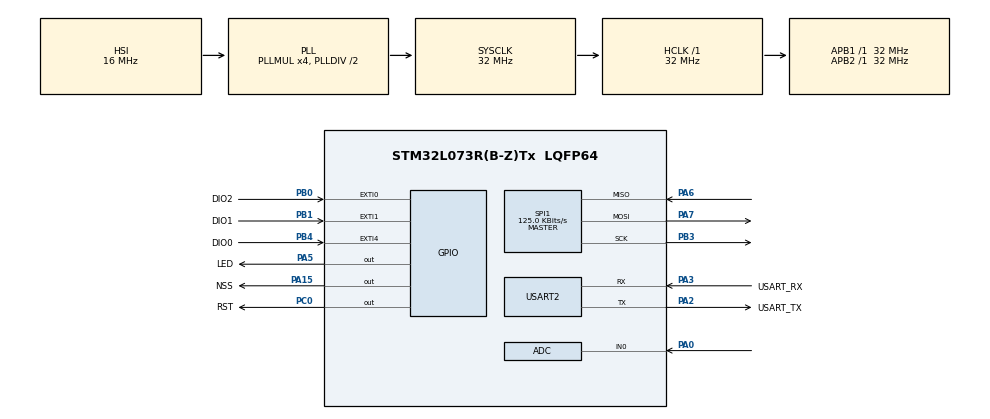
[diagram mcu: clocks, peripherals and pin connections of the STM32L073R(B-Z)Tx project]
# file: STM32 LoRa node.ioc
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Mcu.Family=STM32L0
Mcu.Name=STM32L073R(B-Z)Tx
Mcu.Package=LQFP64
NVIC.EXTI0_1_IRQn=true\:0\:0\:false\:false\:true\:true\:true
NVIC.EXTI4_15_IRQn=true\:0\:0\:false\:false\:true\:true\:true
NVIC.TIM21_IRQn=true\:0\:0\:false\:false\:true\:true\:true
PA0.Mode=IN0
PA0.Signal=ADC_IN0
PA13.GPIO_Label=TMS
PA13.Mode=Serial_Wire
PA13.Signal=SYS_SWDIO
PA14.GPIO_Label=TCK
PA14.Mode=Serial_Wire
PA14.Signal=SYS_SWCLK
PA15.GPIO_Label=NSS
PA15.Signal=GPIO_Output
PA2.GPIO_Label=USART_TX
PA2.Mode=Asynchronous
PA2.Signal=USART2_TX
PA3.GPIO_Label=USART_RX
PA3.Mode=Asynchronous
PA3.Signal=USART2_RX
PA5.GPIO_Label=LED
PA5.Signal=GPIO_Output
PA6.Mode=Full_Duplex_Master
PA6.Signal=SPI1_MISO
PA7.Mode=Full_Duplex_Master
PA7.Signal=SPI1_MOSI
PB0.GPIO_Label=DIO2
PB0.Signal=GPXTI0
PB1.GPIO_Label=DIO1
PB1.Signal=GPXTI1
PB3.Mode=Full_Duplex_Master
PB3.Signal=SPI1_SCK
PB4.GPIO_Label=DIO0
PB4.Signal=GPXTI4
PC0.GPIO_Label=RST
PC0.Signal=GPIO_Output
PC14-OSC32_IN.Mode=LSE-External-Oscillator
PC14-OSC32_IN.Signal=RCC_OSC32_IN
PC15-OSC32_OUT.Mode=LSE-External-Oscillator
PC15-OSC32_OUT.Signal=RCC_OSC32_OUT
ProjectManager.HeapSize=0x200
ProjectManager.StackSize=0x400
ProjectManager.TargetToolchain=STM32CubeIDE
RCC.AHBFreq_Value=32000000
RCC.APB1Freq_Value=32000000
RCC.APB1TimFreq_Value=32000000
RCC.APB2Freq_Value=32000000
RCC.APB2TimFreq_Value=32000000
RCC.HCLKFreq_Value=32000000
RCC.HSE_VALUE=8000000
RCC.HSI16_VALUE=16000000
RCC.HSI48_VALUE=48000000
RCC.HSI_VALUE=16000000
RCC.MSI_VALUE=2097000
RCC.PLLMUL=RCC_PLLMUL_4
RCC.SYSCLKFreq_VALUE=32000000
RCC.SYSCLKSource=RCC_SYSCLKSOURCE_PLLCLK
RCC.VCOOutputFreq_Value=64000000
SPI1.BaudRatePrescaler=SPI_BAUDRATEPRESCALER_256
SPI1.CalculateBaudRate=125.0 KBits/s
SPI1.Direction=SPI_DIRECTION_2LINES
SPI1.Mode=SPI_MODE_MASTER
SPI1.VirtualType=VM_MASTER
TIM21.Channel-Output\ Compare1\ No\ Output=TIM_CHANNEL_1
TIM21.Period=65535 - 1
TIM21.Prescaler=1000 - 1
USART2.VirtualMode-Asynchronous=VM_ASYNC
VP_TIM21_VS_ClockSourceINT.Mode=Internal
VP_TIM21_VS_no_output1.Mode=Output Compare1 No Output
board=NUCLEO-L073RZ

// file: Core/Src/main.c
/* USER CODE BEGIN Header */
/**
  ******************************************************************************
  * @file           : main.c
  * @brief          : Main program body
  ******************************************************************************
  * @attention
  *
  * <h2><center>&copy; Copyright (c) 2020 STMicroelectronics.
  * All rights reserved.</center></h2>
  *
  * This software component is licensed by ST under BSD 3-Clause license,
  * the "License"; You may not use this file except in compliance with the
  * License. You may obtain a copy of the License at:
  *                        opensource.org/licenses/BSD-3-Clause
  *
  ******************************************************************************
  */
/* USER CODE END Header */
#include "main.h"

/* USER CODE BEGIN Includes */
#include "lmic.h"
#include "sdp800.h"
#include "debug.h"
#include <stdio.h>
/* USER CODE END Includes */

ADC_HandleTypeDef hadc;

SPI_HandleTypeDef hspi1;

TIM_HandleTypeDef htim21;

UART_HandleTypeDef huart2;

/* USER CODE BEGIN PV */

Error error;
float diffPressure;
float temperature;

//int32_t temperature;
//uint32_t pressure, humidity;
//uint16_t battery_level;

__uint8_t repeat_period = 1; //number of seconds to wait before measurement loop repetition

/* Private variables ---------------------------------------------------------*/
// application router ID (LSBF)  < ------- IMPORTANT
static const u1_t APPEUI[8]  = { 0xB2, 0x5C, 0x03, 0xD0, 0x7E, 0xD5, 0xB3, 0x70 };
// unique device ID (LSBF)       < ------- IMPORTANT
static const u1_t DEVEUI[8]  = { 0x06, 0x14, 0xA0, 0x16, 0x20, 0xD4, 0x8A, 0x00 };

// device-specific AES key (derived from device EUI)
static const u1_t DEVKEY[16] = { 0x7A, 0x7F, 0x99, 0x33, 0xD6, 0x59, 0x1D, 0x6E, 0xDA, 0x75, 0x01, 0x19, 0x41, 0x64, 0x21, 0x44 };

/* USER CODE END PV */

void SystemClock_Config(void);
static void MX_GPIO_Init(void);
static void MX_USART2_UART_Init(void);
static void MX_SPI1_Init(void);
static void MX_TIM21_Init(void);
static void MX_ADC_Init(void);

/* USER CODE BEGIN 0 */
// provide application router ID (8 bytes, LSBF)
void os_getArtEui (u1_t* buf) {
    memcpy(buf, APPEUI, 8);
}

// provide device ID (8 bytes, LSBF)
void os_getDevEui (u1_t* buf) {
    memcpy(buf, DEVEUI, 8);
}

// provide device key (16 bytes)
void os_getDevKey (u1_t* buf) {
    memcpy(buf, DEVKEY, 16);
}

void initsensor(){
	// init sensors
	Sdp800_Init(0x25);
	Sdp800_SoftReset();
	error = Sdp800_StartContinousMeasurement(SDP800_TEMPCOMP_MASS_FLOW,
		                                             SDP800_AVERAGING_TILL_READ);
	if (error == ERROR_NONE)
		debug_str("SDP800 initialized\n\r");
	else
		debug_str("SDP800 failed to initialize\n\r");
}

void initfunc (osjob_t* j) {
    // intialize sensor hardware
    initsensor();
    // reset MAC state
    LMIC_reset();
    // start joining
    LMIC_startJoining();
    // init done - onEvent() callback will be invoked...
}

int readsensor(){
	error = Sdp800_ReadMeasurementResults(&diffPressure, &temperature);
	return error == ERROR_NONE;
}

static osjob_t reportjob;

// report sensor value every minute
static void reportfunc (osjob_t* j) {
	// read sensor
	if (readsensor()) {
		// if reading was a success:
		debug_str("Reading success: ");
		debug_f(diffPressure);
		debug_str(", ");
		debug_f(temperature);
		debug_str("\n\r");

		memcpy(LMIC.frame + 0, &diffPressure, 4);
		memcpy(LMIC.frame + 4, &temperature, 4);
		//}
	} else {
		// if reading was unsuccessful
		debug_str("Reading failed\n\r");

		for (int i = 0; i < 8; i++) {
			LMIC.frame[i] = 0xff; // error value
		}
	}

    LMIC_setTxData2(1, LMIC.frame, 8, 0); // (port 1, 8 bytes, unconfirmed)
    // reschedule job after 'repeat_period' seconds
    os_setTimedCallback(j, os_getTime()+sec2osticks(repeat_period), reportfunc);
}

//////////////////////////////////////////////////
// LMIC EVENT CALLBACK
//////////////////////////////////////////////////

void onEvent (ev_t ev) {
    debug_event(ev);

    switch(ev) {

      // network joined, session established
      case EV_JOINING:
       	  debug_str("try joining\r\n");
       	  break;
      case EV_JOINED:
          debug_led(1);
          // kick-off periodic sensor job
          reportfunc(&reportjob);
          break;
      case EV_JOIN_FAILED:
    	  debug_str("join failed\r\n");
    	  break;
      case EV_SCAN_TIMEOUT:
    	  debug_str("EV_SCAN_TIMEOUT\r\n");
		  break;
	  case EV_BEACON_FOUND:
		  debug_str("EV_BEACON_FOUND\r\n");
		  break;
	  case EV_BEACON_MISSED:
		  debug_str("EV_BEACON_MISSED\r\n");
		  break;
	  case EV_BEACON_TRACKED:
		  debug_str("EV_BEACON_TRACKED\r\n");
		  break;
	  case EV_RFU1:
		  debug_str("EV_RFU1\r\n");
		  break;
	  case EV_REJOIN_FAILED:
		  debug_str("EV_REJOIN_FAILED\r\n");
		  break;
	  case EV_TXCOMPLETE:
		  debug_str("EV_TXCOMPLETE (includes waiting for RX windows)\r\n");
		  if (LMIC.txrxFlags & TXRX_ACK)
			  debug_str("Received ack\r\n");
		  if (LMIC.dataLen) {
			  debug_str("Received ");
			  debug_int(LMIC.dataLen);
			  debug_str(" bytes of payload\r\n");
		  }
		  break;
	  case EV_LOST_TSYNC:
		  debug_str("EV_LOST_TSYNC\r\n");
		  break;
	  case EV_RESET:
		  debug_str("EV_RESET\r\n");
		  break;
	  case EV_RXCOMPLETE:
		  // data received in ping slot
		  debug_str("EV_RXCOMPLETE\r\n");
		  break;
	  case EV_LINK_DEAD:
		  debug_str("EV_LINK_DEAD\r\n");
		  break;
	  case EV_LINK_ALIVE:
		  debug_str("EV_LINK_ALIVE\r\n");
		  break;
	  default:
		   debug_str("Unknown event\r\n");
		  break;
    }
}
/* USER CODE END 0 */

int main(void)
{

  /* MCU Configuration--------------------------------------------------------*/

  /* Reset of all peripherals, Initializes the Flash interface and the Systick. */
  HAL_Init();

  /* Configure the system clock */
  SystemClock_Config();

  /* Initialize all configured peripherals */
  MX_GPIO_Init();
  MX_USART2_UART_Init();
  MX_SPI1_Init();
  MX_TIM21_Init();
  MX_ADC_Init();
  /* USER CODE BEGIN 2 */

  HAL_TIM_Base_Start_IT(&htim21);    // <-----------  change to your setup
   __HAL_SPI_ENABLE(&hspi1);         // <-----------  change to your setup

   osjob_t initjob;

   // initialize runtime env
   os_init();

   // initialize debug library
   debug_init();

   // setup initial job
   os_setCallback(&initjob, initfunc);

   Sdp800_Init(0x25); // initialize sensor module with address 0x25

   // execute scheduled jobs and events
   os_runloop();

   // (not reached)
   return 0;
  /* USER CODE END 2 */

  /* Infinite loop */
  while (1)
  {

	    	  }
}

void SystemClock_Config(void)
{
  RCC_OscInitTypeDef RCC_OscInitStruct = {0};
  RCC_ClkInitTypeDef RCC_ClkInitStruct = {0};
  RCC_PeriphCLKInitTypeDef PeriphClkInit = {0};

  /** Configure the main internal regulator output voltage
  */
  __HAL_PWR_VOLTAGESCALING_CONFIG(PWR_REGULATOR_VOLTAGE_SCALE1);
  /** Initializes the RCC Oscillators according to the specified parameters
  * in the RCC_OscInitTypeDef structure.
  */
  RCC_OscInitStruct.OscillatorType = RCC_OSCILLATORTYPE_HSI;
  RCC_OscInitStruct.HSIState = RCC_HSI_ON;
  RCC_OscInitStruct.HSICalibrationValue = RCC_HSICALIBRATION_DEFAULT;
  RCC_OscInitStruct.PLL.PLLState = RCC_PLL_ON;
  RCC_OscInitStruct.PLL.PLLSource = RCC_PLLSOURCE_HSI;
  RCC_OscInitStruct.PLL.PLLMUL = RCC_PLLMUL_4;
  RCC_OscInitStruct.PLL.PLLDIV = RCC_PLLDIV_2;
  if (HAL_RCC_OscConfig(&RCC_OscInitStruct) != HAL_OK)
  {
    Error_Handler();
  }
  /** Initializes the CPU, AHB and APB buses clocks
  */
  RCC_ClkInitStruct.ClockType = RCC_CLOCKTYPE_HCLK|RCC_CLOCKTYPE_SYSCLK
                              |RCC_CLOCKTYPE_PCLK1|RCC_CLOCKTYPE_PCLK2;
  RCC_ClkInitStruct.SYSCLKSource = RCC_SYSCLKSOURCE_PLLCLK;
  RCC_ClkInitStruct.AHBCLKDivider = RCC_SYSCLK_DIV1;
  RCC_ClkInitStruct.APB1CLKDivider = RCC_HCLK_DIV1;
  RCC_ClkInitStruct.APB2CLKDivider = RCC_HCLK_DIV1;

  if (HAL_RCC_ClockConfig(&RCC_ClkInitStruct, FLASH_LATENCY_1) != HAL_OK)
  {
    Error_Handler();
  }
  PeriphClkInit.PeriphClockSelection = RCC_PERIPHCLK_USART2;
  PeriphClkInit.Usart2ClockSelection = RCC_USART2CLKSOURCE_PCLK1;
  if (HAL_RCCEx_PeriphCLKConfig(&PeriphClkInit) != HAL_OK)
  {
    Error_Handler();
  }
}

static void MX_ADC_Init(void)
{

  ADC_ChannelConfTypeDef sConfig = {0};

  /** Configure the global features of the ADC (Clock, Resolution, Data Alignment and number of conversion)
  */
  hadc.Instance = ADC1;
  hadc.Init.OversamplingMode = DISABLE;
  hadc.Init.ClockPrescaler = ADC_CLOCK_SYNC_PCLK_DIV2;
  hadc.Init.Resolution = ADC_RESOLUTION_12B;
  hadc.Init.SamplingTime = ADC_SAMPLETIME_1CYCLE_5;
  hadc.Init.ScanConvMode = ADC_SCAN_DIRECTION_FORWARD;
  hadc.Init.DataAlign = ADC_DATAALIGN_RIGHT;
  hadc.Init.ContinuousConvMode = DISABLE;
  hadc.Init.DiscontinuousConvMode = DISABLE;
  hadc.Init.ExternalTrigConvEdge = ADC_EXTERNALTRIGCONVEDGE_NONE;
  hadc.Init.ExternalTrigConv = ADC_SOFTWARE_START;
  hadc.Init.DMAContinuousRequests = DISABLE;
  hadc.Init.EOCSelection = ADC_EOC_SINGLE_CONV;
  hadc.Init.Overrun = ADC_OVR_DATA_PRESERVED;
  hadc.Init.LowPowerAutoWait = DISABLE;
  hadc.Init.LowPowerFrequencyMode = DISABLE;
  hadc.Init.LowPowerAutoPowerOff = DISABLE;
  if (HAL_ADC_Init(&hadc) != HAL_OK)
  {
    Error_Handler();
  }
  /** Configure for the selected ADC regular channel to be converted.
  */
  sConfig.Channel = ADC_CHANNEL_0;
  sConfig.Rank = ADC_RANK_CHANNEL_NUMBER;
  if (HAL_ADC_ConfigChannel(&hadc, &sConfig) != HAL_OK)
  {
    Error_Handler();
  }

}

static void MX_SPI1_Init(void)
{

  /* SPI1 parameter configuration*/
  hspi1.Instance = SPI1;
  hspi1.Init.Mode = SPI_MODE_MASTER;
  hspi1.Init.Direction = SPI_DIRECTION_2LINES;
  hspi1.Init.DataSize = SPI_DATASIZE_8BIT;
  hspi1.Init.CLKPolarity = SPI_POLARITY_LOW;
  hspi1.Init.CLKPhase = SPI_PHASE_1EDGE;
  hspi1.Init.NSS = SPI_NSS_SOFT;
  hspi1.Init.BaudRatePrescaler = SPI_BAUDRATEPRESCALER_256;
  hspi1.Init.FirstBit = SPI_FIRSTBIT_MSB;
  hspi1.Init.TIMode = SPI_TIMODE_DISABLE;
  hspi1.Init.CRCCalculation = SPI_CRCCALCULATION_DISABLE;
  hspi1.Init.CRCPolynomial = 7;
  if (HAL_SPI_Init(&hspi1) != HAL_OK)
  {
    Error_Handler();
  }

}

static void MX_TIM21_Init(void)
{

  TIM_ClockConfigTypeDef sClockSourceConfig = {0};
  TIM_MasterConfigTypeDef sMasterConfig = {0};
  TIM_OC_InitTypeDef sConfigOC = {0};

  htim21.Instance = TIM21;
  htim21.Init.Prescaler = 1000 - 1;
  htim21.Init.CounterMode = TIM_COUNTERMODE_UP;
  htim21.Init.Period = 65535 - 1;
  htim21.Init.ClockDivision = TIM_CLOCKDIVISION_DIV1;
  htim21.Init.AutoReloadPreload = TIM_AUTORELOAD_PRELOAD_DISABLE;
  if (HAL_TIM_Base_Init(&htim21) != HAL_OK)
  {
    Error_Handler();
  }
  sClockSourceConfig.ClockSource = TIM_CLOCKSOURCE_INTERNAL;
  if (HAL_TIM_ConfigClockSource(&htim21, &sClockSourceConfig) != HAL_OK)
  {
    Error_Handler();
  }
  if (HAL_TIM_OC_Init(&htim21) != HAL_OK)
  {
    Error_Handler();
  }
  sMasterConfig.MasterOutputTrigger = TIM_TRGO_RESET;
  sMasterConfig.MasterSlaveMode = TIM_MASTERSLAVEMODE_DISABLE;
  if (HAL_TIMEx_MasterConfigSynchronization(&htim21, &sMasterConfig) != HAL_OK)
  {
    Error_Handler();
  }
  sConfigOC.OCMode = TIM_OCMODE_TIMING;
  sConfigOC.Pulse = 0;
  sConfigOC.OCPolarity = TIM_OCPOLARITY_HIGH;
  sConfigOC.OCFastMode = TIM_OCFAST_DISABLE;
  if (HAL_TIM_OC_ConfigChannel(&htim21, &sConfigOC, TIM_CHANNEL_1) != HAL_OK)
  {
    Error_Handler();
  }

}

static void MX_USART2_UART_Init(void)
{

  huart2.Instance = USART2;
  huart2.Init.BaudRate = 115200;
  huart2.Init.WordLength = UART_WORDLENGTH_8B;
  huart2.Init.StopBits = UART_STOPBITS_1;
  huart2.Init.Parity = UART_PARITY_NONE;
  huart2.Init.Mode = UART_MODE_TX_RX;
  huart2.Init.HwFlowCtl = UART_HWCONTROL_NONE;
  huart2.Init.OverSampling = UART_OVERSAMPLING_16;
  huart2.Init.OneBitSampling = UART_ONE_BIT_SAMPLE_DISABLE;
  huart2.AdvancedInit.AdvFeatureInit = UART_ADVFEATURE_NO_INIT;
  if (HAL_UART_Init(&huart2) != HAL_OK)
  {
    Error_Handler();
  }

}

static void MX_GPIO_Init(void)
{
  GPIO_InitTypeDef GPIO_InitStruct = {0};

  /* GPIO Ports Clock Enable */
  __HAL_RCC_GPIOC_CLK_ENABLE();
  __HAL_RCC_GPIOA_CLK_ENABLE();
  __HAL_RCC_GPIOB_CLK_ENABLE();

  /*Configure GPIO pin Output Level */
  HAL_GPIO_WritePin(RST_GPIO_Port, RST_Pin, GPIO_PIN_RESET);

  /*Configure GPIO pin Output Level */
  HAL_GPIO_WritePin(GPIOA, LED_Pin|NSS_Pin, GPIO_PIN_RESET);

  /*Configure GPIO pin : RST_Pin */
  GPIO_InitStruct.Pin = RST_Pin;
  GPIO_InitStruct.Mode = GPIO_MODE_OUTPUT_PP;
  GPIO_InitStruct.Pull = GPIO_NOPULL;
  GPIO_InitStruct.Speed = GPIO_SPEED_FREQ_LOW;
  HAL_GPIO_Init(RST_GPIO_Port, &GPIO_InitStruct);

  /*Configure GPIO pins : LED_Pin NSS_Pin */
  GPIO_InitStruct.Pin = LED_Pin|NSS_Pin;
  GPIO_InitStruct.Mode = GPIO_MODE_OUTPUT_PP;
  GPIO_InitStruct.Pull = GPIO_NOPULL;
  GPIO_InitStruct.Speed = GPIO_SPEED_FREQ_LOW;
  HAL_GPIO_Init(GPIOA, &GPIO_InitStruct);

  /*Configure GPIO pins : DIO2_Pin DIO1_Pin DIO0_Pin */
  GPIO_InitStruct.Pin = DIO2_Pin|DIO1_Pin|DIO0_Pin;
  GPIO_InitStruct.Mode = GPIO_MODE_IT_RISING;
  GPIO_InitStruct.Pull = GPIO_NOPULL;
  HAL_GPIO_Init(GPIOB, &GPIO_InitStruct);

  /**/
  GPIO_InitStruct.Pin = GPIO_PIN_8;
  GPIO_InitStruct.Mode = GPIO_MODE_OUTPUT_OD;
  GPIO_InitStruct.Speed = GPIO_SPEED_FREQ_LOW;
  GPIO_InitStruct.Pull = GPIO_PULLUP;
  HAL_GPIO_Init(GPIOB, &GPIO_InitStruct);

  /**/
  GPIO_InitStruct.Pin = GPIO_PIN_9;
  GPIO_InitStruct.Mode = GPIO_MODE_OUTPUT_OD;
  GPIO_InitStruct.Speed = GPIO_SPEED_FREQ_LOW;
  GPIO_InitStruct.Pull = GPIO_PULLUP;
  HAL_GPIO_Init(GPIOB, &GPIO_InitStruct);

  /* EXTI interrupt init*/
  HAL_NVIC_SetPriority(EXTI0_1_IRQn, 0, 0);
  HAL_NVIC_EnableIRQ(EXTI0_1_IRQn);

  HAL_NVIC_SetPriority(EXTI4_15_IRQn, 0, 0);
  HAL_NVIC_EnableIRQ(EXTI4_15_IRQn);

}

void Error_Handler(void)
{
}

/************************ (C) COPYRIGHT STMicroelectronics *****END OF FILE****/
